VERSION 5.7 ;
  NOWIREEXTENSIONATPIN ON ;
  DIVIDERCHAR "/" ;
  BUSBITCHARS "[]" ;
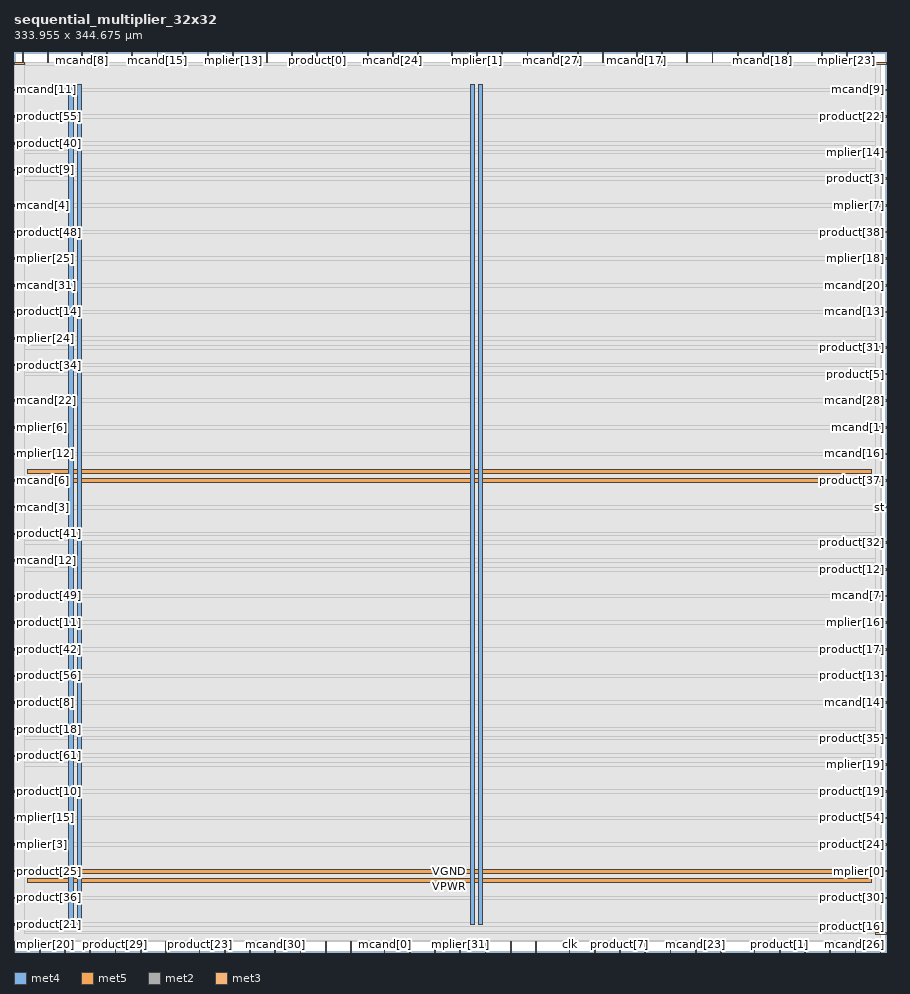
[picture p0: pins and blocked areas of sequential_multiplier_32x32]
MACRO sequential_multiplier_32x32
  CLASS BLOCK ;
  FOREIGN sequential_multiplier_32x32 ;
  ORIGIN 0.000 0.000 ;
  SIZE 333.955 BY 344.675 ;
  PIN VGND
    DIRECTION INOUT ;
    USE GROUND ;
    PORT
      LAYER met4 ;
        RECT 24.340 10.640 25.940 332.080 ;
    END
    PORT
      LAYER met4 ;
        RECT 177.940 10.640 179.540 332.080 ;
    END
    PORT
      LAYER met5 ;
        RECT 5.280 30.030 328.220 31.630 ;
    END
    PORT
      LAYER met5 ;
        RECT 5.280 183.210 328.220 184.810 ;
    END
  END VGND
  PIN VPWR
    DIRECTION INOUT ;
    USE POWER ;
    PORT
      LAYER met4 ;
        RECT 21.040 10.640 22.640 332.080 ;
    END
    PORT
      LAYER met4 ;
        RECT 174.640 10.640 176.240 332.080 ;
    END
    PORT
      LAYER met5 ;
        RECT 5.280 26.730 328.220 28.330 ;
    END
    PORT
      LAYER met5 ;
        RECT 5.280 179.910 328.220 181.510 ;
    END
  END VPWR
  PIN clk
    DIRECTION INPUT ;
    USE SIGNAL ;
    ANTENNAGATEAREA 0.852000 ;
    PORT
      LAYER met2 ;
        RECT 212.610 0.000 212.890 4.000 ;
    END
  END clk
  PIN done
    DIRECTION OUTPUT TRISTATE ;
    USE SIGNAL ;
    ANTENNADIFFAREA 0.795200 ;
    PORT
      LAYER met2 ;
        RECT 90.250 0.000 90.530 4.000 ;
    END
  END done
  PIN mcand[0]
    DIRECTION INPUT ;
    USE SIGNAL ;
    ANTENNAGATEAREA 0.213000 ;
    PORT
      LAYER met2 ;
        RECT 141.770 0.000 142.050 4.000 ;
    END
  END mcand[0]
  PIN mcand[10]
    DIRECTION INPUT ;
    USE SIGNAL ;
    ANTENNAGATEAREA 0.213000 ;
    PORT
      LAYER met2 ;
        RECT 199.730 0.000 200.010 4.000 ;
    END
  END mcand[10]
  PIN mcand[11]
    DIRECTION INPUT ;
    USE SIGNAL ;
    ANTENNAGATEAREA 0.159000 ;
    PORT
      LAYER met3 ;
        RECT 0.000 329.840 4.000 330.440 ;
    END
  END mcand[11]
  PIN mcand[12]
    DIRECTION INPUT ;
    USE SIGNAL ;
    ANTENNAGATEAREA 0.159000 ;
    PORT
      LAYER met3 ;
        RECT 0.000 149.640 4.000 150.240 ;
    END
  END mcand[12]
  PIN mcand[13]
    DIRECTION INPUT ;
    USE SIGNAL ;
    ANTENNAGATEAREA 0.213000 ;
    PORT
      LAYER met3 ;
        RECT 329.955 244.840 333.955 245.440 ;
    END
  END mcand[13]
  PIN mcand[14]
    DIRECTION INPUT ;
    USE SIGNAL ;
    ANTENNAGATEAREA 0.213000 ;
    PORT
      LAYER met3 ;
        RECT 329.955 95.240 333.955 95.840 ;
    END
  END mcand[14]
  PIN mcand[15]
    DIRECTION INPUT ;
    USE SIGNAL ;
    ANTENNAGATEAREA 0.159000 ;
    PORT
      LAYER met2 ;
        RECT 54.830 340.675 55.110 344.675 ;
    END
  END mcand[15]
  PIN mcand[16]
    DIRECTION INPUT ;
    USE SIGNAL ;
    ANTENNAGATEAREA 0.213000 ;
    PORT
      LAYER met3 ;
        RECT 329.955 190.440 333.955 191.040 ;
    END
  END mcand[16]
  PIN mcand[17]
    DIRECTION INPUT ;
    USE SIGNAL ;
    ANTENNAGATEAREA 0.196500 ;
    PORT
      LAYER met2 ;
        RECT 238.370 340.675 238.650 344.675 ;
    END
  END mcand[17]
  PIN mcand[18]
    DIRECTION INPUT ;
    USE SIGNAL ;
    ANTENNAGATEAREA 0.196500 ;
    PORT
      LAYER met2 ;
        RECT 286.670 340.675 286.950 344.675 ;
    END
  END mcand[18]
  PIN mcand[19]
    DIRECTION INPUT ;
    USE SIGNAL ;
    ANTENNAGATEAREA 0.213000 ;
    PORT
      LAYER met2 ;
        RECT 328.530 340.675 328.810 344.675 ;
    END
  END mcand[19]
  PIN mcand[1]
    DIRECTION INPUT ;
    USE SIGNAL ;
    ANTENNAGATEAREA 0.213000 ;
    PORT
      LAYER met3 ;
        RECT 329.955 200.640 333.955 201.240 ;
    END
  END mcand[1]
  PIN mcand[20]
    DIRECTION INPUT ;
    USE SIGNAL ;
    ANTENNAGATEAREA 0.126000 ;
    PORT
      LAYER met3 ;
        RECT 329.955 255.040 333.955 255.640 ;
    END
  END mcand[20]
  PIN mcand[21]
    DIRECTION INPUT ;
    USE SIGNAL ;
    ANTENNAGATEAREA 0.159000 ;
    PORT
      LAYER met2 ;
        RECT 80.590 0.000 80.870 4.000 ;
    END
  END mcand[21]
  PIN mcand[22]
    DIRECTION INPUT ;
    USE SIGNAL ;
    ANTENNAGATEAREA 0.213000 ;
    PORT
      LAYER met3 ;
        RECT 0.000 210.840 4.000 211.440 ;
    END
  END mcand[22]
  PIN mcand[23]
    DIRECTION INPUT ;
    USE SIGNAL ;
    ANTENNAGATEAREA 0.159000 ;
    PORT
      LAYER met2 ;
        RECT 260.910 0.000 261.190 4.000 ;
    END
  END mcand[23]
  PIN mcand[24]
    DIRECTION INPUT ;
    USE SIGNAL ;
    ANTENNAGATEAREA 0.213000 ;
    PORT
      LAYER met2 ;
        RECT 144.990 340.675 145.270 344.675 ;
    END
  END mcand[24]
  PIN mcand[25]
    DIRECTION INPUT ;
    USE SIGNAL ;
    ANTENNAGATEAREA 0.159000 ;
    PORT
      LAYER met2 ;
        RECT 322.090 0.000 322.370 4.000 ;
    END
  END mcand[25]
  PIN mcand[26]
    DIRECTION INPUT ;
    USE SIGNAL ;
    ANTENNAGATEAREA 0.159000 ;
    PORT
      LAYER met2 ;
        RECT 331.750 0.000 332.030 4.000 ;
    END
  END mcand[26]
  PIN mcand[27]
    DIRECTION INPUT ;
    USE SIGNAL ;
    ANTENNAGATEAREA 0.159000 ;
    PORT
      LAYER met2 ;
        RECT 206.170 340.675 206.450 344.675 ;
    END
  END mcand[27]
  PIN mcand[28]
    DIRECTION INPUT ;
    USE SIGNAL ;
    ANTENNAGATEAREA 0.213000 ;
    PORT
      LAYER met3 ;
        RECT 329.955 210.840 333.955 211.440 ;
    END
  END mcand[28]
  PIN mcand[29]
    DIRECTION INPUT ;
    USE SIGNAL ;
    ANTENNAGATEAREA 0.213000 ;
    PORT
      LAYER met2 ;
        RECT 74.150 340.675 74.430 344.675 ;
    END
  END mcand[29]
  PIN mcand[2]
    DIRECTION INPUT ;
    USE SIGNAL ;
    ANTENNAGATEAREA 0.213000 ;
    PORT
      LAYER met2 ;
        RECT 283.450 0.000 283.730 4.000 ;
    END
  END mcand[2]
  PIN mcand[30]
    DIRECTION INPUT ;
    USE SIGNAL ;
    ANTENNAGATEAREA 0.213000 ;
    PORT
      LAYER met2 ;
        RECT 99.910 0.000 100.190 4.000 ;
    END
  END mcand[30]
  PIN mcand[31]
    DIRECTION INPUT ;
    USE SIGNAL ;
    ANTENNAGATEAREA 0.126000 ;
    PORT
      LAYER met3 ;
        RECT 0.000 255.040 4.000 255.640 ;
    END
  END mcand[31]
  PIN mcand[3]
    DIRECTION INPUT ;
    USE SIGNAL ;
    ANTENNAGATEAREA 0.213000 ;
    PORT
      LAYER met3 ;
        RECT 0.000 170.040 4.000 170.640 ;
    END
  END mcand[3]
  PIN mcand[4]
    DIRECTION INPUT ;
    USE SIGNAL ;
    ANTENNAGATEAREA 0.159000 ;
    PORT
      LAYER met3 ;
        RECT 0.000 285.640 4.000 286.240 ;
    END
  END mcand[4]
  PIN mcand[5]
    DIRECTION INPUT ;
    USE SIGNAL ;
    ANTENNAGATEAREA 0.213000 ;
    PORT
      LAYER met2 ;
        RECT 125.670 340.675 125.950 344.675 ;
    END
  END mcand[5]
  PIN mcand[6]
    DIRECTION INPUT ;
    USE SIGNAL ;
    ANTENNAGATEAREA 0.159000 ;
    PORT
      LAYER met3 ;
        RECT 0.000 180.240 4.000 180.840 ;
    END
  END mcand[6]
  PIN mcand[7]
    DIRECTION INPUT ;
    USE SIGNAL ;
    ANTENNAGATEAREA 0.213000 ;
    PORT
      LAYER met3 ;
        RECT 329.955 136.040 333.955 136.640 ;
    END
  END mcand[7]
  PIN mcand[8]
    DIRECTION INPUT ;
    USE SIGNAL ;
    ANTENNAGATEAREA 0.126000 ;
    PORT
      LAYER met2 ;
        RECT 25.850 340.675 26.130 344.675 ;
    END
  END mcand[8]
  PIN mcand[9]
    DIRECTION INPUT ;
    USE SIGNAL ;
    ANTENNAGATEAREA 0.159000 ;
    PORT
      LAYER met3 ;
        RECT 329.955 329.840 333.955 330.440 ;
    END
  END mcand[9]
  PIN mplier[0]
    DIRECTION INPUT ;
    USE SIGNAL ;
    ANTENNAGATEAREA 0.213000 ;
    PORT
      LAYER met3 ;
        RECT 329.955 30.640 333.955 31.240 ;
    END
  END mplier[0]
  PIN mplier[10]
    DIRECTION INPUT ;
    USE SIGNAL ;
    ANTENNAGATEAREA 0.213000 ;
    PORT
      LAYER met2 ;
        RECT 45.170 340.675 45.450 344.675 ;
    END
  END mplier[10]
  PIN mplier[11]
    DIRECTION INPUT ;
    USE SIGNAL ;
    ANTENNAGATEAREA 0.213000 ;
    PORT
      LAYER met2 ;
        RECT 135.330 340.675 135.610 344.675 ;
    END
  END mplier[11]
  PIN mplier[12]
    DIRECTION INPUT ;
    USE SIGNAL ;
    ANTENNAGATEAREA 0.126000 ;
    PORT
      LAYER met3 ;
        RECT 0.000 190.440 4.000 191.040 ;
    END
  END mplier[12]
  PIN mplier[13]
    DIRECTION INPUT ;
    USE SIGNAL ;
    ANTENNAGATEAREA 0.213000 ;
    PORT
      LAYER met2 ;
        RECT 83.810 340.675 84.090 344.675 ;
    END
  END mplier[13]
  PIN mplier[14]
    DIRECTION INPUT ;
    USE SIGNAL ;
    ANTENNAGATEAREA 0.213000 ;
    PORT
      LAYER met3 ;
        RECT 329.955 306.040 333.955 306.640 ;
    END
  END mplier[14]
  PIN mplier[15]
    DIRECTION INPUT ;
    USE SIGNAL ;
    ANTENNAGATEAREA 0.196500 ;
    PORT
      LAYER met3 ;
        RECT 0.000 51.040 4.000 51.640 ;
    END
  END mplier[15]
  PIN mplier[16]
    DIRECTION INPUT ;
    USE SIGNAL ;
    ANTENNAGATEAREA 0.196500 ;
    PORT
      LAYER met3 ;
        RECT 329.955 125.840 333.955 126.440 ;
    END
  END mplier[16]
  PIN mplier[17]
    DIRECTION INPUT ;
    USE SIGNAL ;
    ANTENNAGATEAREA 0.159000 ;
    PORT
      LAYER met2 ;
        RECT 309.210 340.675 309.490 344.675 ;
    END
  END mplier[17]
  PIN mplier[18]
    DIRECTION INPUT ;
    USE SIGNAL ;
    ANTENNAGATEAREA 0.159000 ;
    PORT
      LAYER met3 ;
        RECT 329.955 265.240 333.955 265.840 ;
    END
  END mplier[18]
  PIN mplier[19]
    DIRECTION INPUT ;
    USE SIGNAL ;
    ANTENNAGATEAREA 0.196500 ;
    PORT
      LAYER met3 ;
        RECT 329.955 71.440 333.955 72.040 ;
    END
  END mplier[19]
  PIN mplier[1]
    DIRECTION INPUT ;
    USE SIGNAL ;
    ANTENNAGATEAREA 0.213000 ;
    PORT
      LAYER met2 ;
        RECT 177.190 340.675 177.470 344.675 ;
    END
  END mplier[1]
  PIN mplier[20]
    DIRECTION INPUT ;
    USE SIGNAL ;
    ANTENNAGATEAREA 0.213000 ;
    PORT
      LAYER met2 ;
        RECT 9.750 0.000 10.030 4.000 ;
    END
  END mplier[20]
  PIN mplier[21]
    DIRECTION INPUT ;
    USE SIGNAL ;
    ANTENNAGATEAREA 0.213000 ;
    PORT
      LAYER met2 ;
        RECT 225.490 340.675 225.770 344.675 ;
    END
  END mplier[21]
  PIN mplier[22]
    DIRECTION INPUT ;
    USE SIGNAL ;
    ANTENNAGATEAREA 0.196500 ;
    PORT
      LAYER met2 ;
        RECT 241.590 0.000 241.870 4.000 ;
    END
  END mplier[22]
  PIN mplier[23]
    DIRECTION INPUT ;
    USE SIGNAL ;
    ANTENNAGATEAREA 0.159000 ;
    PORT
      LAYER met2 ;
        RECT 318.870 340.675 319.150 344.675 ;
    END
  END mplier[23]
  PIN mplier[24]
    DIRECTION INPUT ;
    USE SIGNAL ;
    ANTENNAGATEAREA 0.159000 ;
    PORT
      LAYER met3 ;
        RECT 0.000 234.640 4.000 235.240 ;
    END
  END mplier[24]
  PIN mplier[25]
    DIRECTION INPUT ;
    USE SIGNAL ;
    ANTENNAGATEAREA 0.159000 ;
    PORT
      LAYER met3 ;
        RECT 0.000 265.240 4.000 265.840 ;
    END
  END mplier[25]
  PIN mplier[26]
    DIRECTION INPUT ;
    USE SIGNAL ;
    ANTENNAGATEAREA 0.159000 ;
    PORT
      LAYER met2 ;
        RECT 12.970 340.675 13.250 344.675 ;
    END
  END mplier[26]
  PIN mplier[27]
    DIRECTION INPUT ;
    USE SIGNAL ;
    ANTENNAGATEAREA 0.196500 ;
    PORT
      LAYER met2 ;
        RECT 128.890 0.000 129.170 4.000 ;
    END
  END mplier[27]
  PIN mplier[28]
    DIRECTION INPUT ;
    USE SIGNAL ;
    ANTENNAGATEAREA 0.213000 ;
    PORT
      LAYER met2 ;
        RECT 167.530 340.675 167.810 344.675 ;
    END
  END mplier[28]
  PIN mplier[29]
    DIRECTION INPUT ;
    USE SIGNAL ;
    ANTENNAGATEAREA 0.159000 ;
    PORT
      LAYER met2 ;
        RECT 106.350 340.675 106.630 344.675 ;
    END
  END mplier[29]
  PIN mplier[2]
    DIRECTION INPUT ;
    USE SIGNAL ;
    ANTENNAGATEAREA 0.126000 ;
    PORT
      LAYER met2 ;
        RECT 48.390 0.000 48.670 4.000 ;
    END
  END mplier[2]
  PIN mplier[30]
    DIRECTION INPUT ;
    USE SIGNAL ;
    ANTENNAGATEAREA 0.159000 ;
    PORT
      LAYER met3 ;
        RECT 329.955 340.040 333.955 340.640 ;
    END
  END mplier[30]
  PIN mplier[31]
    DIRECTION INPUT ;
    USE SIGNAL ;
    ANTENNAGATEAREA 0.196500 ;
    PORT
      LAYER met2 ;
        RECT 170.750 0.000 171.030 4.000 ;
    END
  END mplier[31]
  PIN mplier[3]
    DIRECTION INPUT ;
    USE SIGNAL ;
    ANTENNAGATEAREA 0.126000 ;
    PORT
      LAYER met3 ;
        RECT 0.000 40.840 4.000 41.440 ;
    END
  END mplier[3]
  PIN mplier[4]
    DIRECTION INPUT ;
    USE SIGNAL ;
    ANTENNAGATEAREA 0.213000 ;
    PORT
      LAYER met2 ;
        RECT 196.510 340.675 196.790 344.675 ;
    END
  END mplier[4]
  PIN mplier[5]
    DIRECTION INPUT ;
    USE SIGNAL ;
    ANTENNAGATEAREA 0.159000 ;
    PORT
      LAYER met2 ;
        RECT 257.690 340.675 257.970 344.675 ;
    END
  END mplier[5]
  PIN mplier[6]
    DIRECTION INPUT ;
    USE SIGNAL ;
    ANTENNAGATEAREA 0.213000 ;
    PORT
      LAYER met3 ;
        RECT 0.000 200.640 4.000 201.240 ;
    END
  END mplier[6]
  PIN mplier[7]
    DIRECTION INPUT ;
    USE SIGNAL ;
    ANTENNAGATEAREA 0.159000 ;
    PORT
      LAYER met3 ;
        RECT 329.955 285.640 333.955 286.240 ;
    END
  END mplier[7]
  PIN mplier[8]
    DIRECTION INPUT ;
    USE SIGNAL ;
    ANTENNAGATEAREA 0.159000 ;
    PORT
      LAYER met2 ;
        RECT 277.010 340.675 277.290 344.675 ;
    END
  END mplier[8]
  PIN mplier[9]
    DIRECTION INPUT ;
    USE SIGNAL ;
    ANTENNAGATEAREA 0.213000 ;
    PORT
      LAYER met2 ;
        RECT 35.510 340.675 35.790 344.675 ;
    END
  END mplier[9]
  PIN product[0]
    DIRECTION OUTPUT TRISTATE ;
    USE SIGNAL ;
    ANTENNADIFFAREA 0.795200 ;
    PORT
      LAYER met2 ;
        RECT 116.010 340.675 116.290 344.675 ;
    END
  END product[0]
  PIN product[10]
    DIRECTION OUTPUT TRISTATE ;
    USE SIGNAL ;
    ANTENNADIFFAREA 0.795200 ;
    PORT
      LAYER met3 ;
        RECT 0.000 61.240 4.000 61.840 ;
    END
  END product[10]
  PIN product[11]
    DIRECTION OUTPUT TRISTATE ;
    USE SIGNAL ;
    ANTENNADIFFAREA 0.795200 ;
    PORT
      LAYER met3 ;
        RECT 0.000 125.840 4.000 126.440 ;
    END
  END product[11]
  PIN product[12]
    DIRECTION OUTPUT TRISTATE ;
    USE SIGNAL ;
    ANTENNADIFFAREA 0.445500 ;
    PORT
      LAYER met3 ;
        RECT 329.955 146.240 333.955 146.840 ;
    END
  END product[12]
  PIN product[13]
    DIRECTION OUTPUT TRISTATE ;
    USE SIGNAL ;
    ANTENNADIFFAREA 0.445500 ;
    PORT
      LAYER met3 ;
        RECT 329.955 105.440 333.955 106.040 ;
    END
  END product[13]
  PIN product[14]
    DIRECTION OUTPUT TRISTATE ;
    USE SIGNAL ;
    ANTENNADIFFAREA 0.795200 ;
    PORT
      LAYER met3 ;
        RECT 0.000 244.840 4.000 245.440 ;
    END
  END product[14]
  PIN product[15]
    DIRECTION OUTPUT TRISTATE ;
    USE SIGNAL ;
    ANTENNADIFFAREA 0.795200 ;
    PORT
      LAYER met2 ;
        RECT 29.070 0.000 29.350 4.000 ;
    END
  END product[15]
  PIN product[16]
    DIRECTION OUTPUT TRISTATE ;
    USE SIGNAL ;
    ANTENNADIFFAREA 0.795200 ;
    PORT
      LAYER met3 ;
        RECT 329.955 6.840 333.955 7.440 ;
    END
  END product[16]
  PIN product[17]
    DIRECTION OUTPUT TRISTATE ;
    USE SIGNAL ;
    ANTENNADIFFAREA 0.795200 ;
    PORT
      LAYER met3 ;
        RECT 329.955 115.640 333.955 116.240 ;
    END
  END product[17]
  PIN product[18]
    DIRECTION OUTPUT TRISTATE ;
    USE SIGNAL ;
    ANTENNADIFFAREA 0.795200 ;
    PORT
      LAYER met3 ;
        RECT 0.000 85.040 4.000 85.640 ;
    END
  END product[18]
  PIN product[19]
    DIRECTION OUTPUT TRISTATE ;
    USE SIGNAL ;
    ANTENNADIFFAREA 0.795200 ;
    PORT
      LAYER met3 ;
        RECT 329.955 61.240 333.955 61.840 ;
    END
  END product[19]
  PIN product[1]
    DIRECTION OUTPUT TRISTATE ;
    USE SIGNAL ;
    ANTENNADIFFAREA 0.795200 ;
    PORT
      LAYER met2 ;
        RECT 293.110 0.000 293.390 4.000 ;
    END
  END product[1]
  PIN product[20]
    DIRECTION OUTPUT TRISTATE ;
    USE SIGNAL ;
    ANTENNADIFFAREA 0.795200 ;
    PORT
      LAYER met2 ;
        RECT 151.430 0.000 151.710 4.000 ;
    END
  END product[20]
  PIN product[21]
    DIRECTION OUTPUT TRISTATE ;
    USE SIGNAL ;
    ANTENNADIFFAREA 0.795200 ;
    PORT
      LAYER met3 ;
        RECT 0.000 10.240 4.000 10.840 ;
    END
  END product[21]
  PIN product[22]
    DIRECTION OUTPUT TRISTATE ;
    USE SIGNAL ;
    ANTENNADIFFAREA 0.445500 ;
    PORT
      LAYER met3 ;
        RECT 329.955 319.640 333.955 320.240 ;
    END
  END product[22]
  PIN product[23]
    DIRECTION OUTPUT TRISTATE ;
    USE SIGNAL ;
    ANTENNADIFFAREA 0.795200 ;
    PORT
      LAYER met2 ;
        RECT 70.930 0.000 71.210 4.000 ;
    END
  END product[23]
  PIN product[24]
    DIRECTION OUTPUT TRISTATE ;
    USE SIGNAL ;
    ANTENNADIFFAREA 0.795200 ;
    PORT
      LAYER met3 ;
        RECT 329.955 40.840 333.955 41.440 ;
    END
  END product[24]
  PIN product[25]
    DIRECTION OUTPUT TRISTATE ;
    USE SIGNAL ;
    ANTENNADIFFAREA 0.795200 ;
    PORT
      LAYER met3 ;
        RECT 0.000 30.640 4.000 31.240 ;
    END
  END product[25]
  PIN product[26]
    DIRECTION OUTPUT TRISTATE ;
    USE SIGNAL ;
    ANTENNADIFFAREA 0.795200 ;
    PORT
      LAYER met2 ;
        RECT 312.430 0.000 312.710 4.000 ;
    END
  END product[26]
  PIN product[27]
    DIRECTION OUTPUT TRISTATE ;
    USE SIGNAL ;
    ANTENNADIFFAREA 0.795200 ;
    PORT
      LAYER met2 ;
        RECT 154.650 340.675 154.930 344.675 ;
    END
  END product[27]
  PIN product[28]
    DIRECTION OUTPUT TRISTATE ;
    USE SIGNAL ;
    ANTENNADIFFAREA 0.795200 ;
    PORT
      LAYER met2 ;
        RECT 251.250 0.000 251.530 4.000 ;
    END
  END product[28]
  PIN product[29]
    DIRECTION OUTPUT TRISTATE ;
    USE SIGNAL ;
    ANTENNADIFFAREA 0.795200 ;
    PORT
      LAYER met2 ;
        RECT 38.730 0.000 39.010 4.000 ;
    END
  END product[29]
  PIN product[2]
    DIRECTION OUTPUT TRISTATE ;
    USE SIGNAL ;
    ANTENNADIFFAREA 0.795200 ;
    PORT
      LAYER met2 ;
        RECT 119.230 0.000 119.510 4.000 ;
    END
  END product[2]
  PIN product[30]
    DIRECTION OUTPUT TRISTATE ;
    USE SIGNAL ;
    ANTENNADIFFAREA 0.445500 ;
    PORT
      LAYER met3 ;
        RECT 329.955 20.440 333.955 21.040 ;
    END
  END product[30]
  PIN product[31]
    DIRECTION OUTPUT TRISTATE ;
    USE SIGNAL ;
    ANTENNADIFFAREA 0.445500 ;
    PORT
      LAYER met3 ;
        RECT 329.955 231.240 333.955 231.840 ;
    END
  END product[31]
  PIN product[32]
    DIRECTION OUTPUT TRISTATE ;
    USE SIGNAL ;
    ANTENNADIFFAREA 0.795200 ;
    PORT
      LAYER met3 ;
        RECT 329.955 156.440 333.955 157.040 ;
    END
  END product[32]
  PIN product[33]
    DIRECTION OUTPUT TRISTATE ;
    USE SIGNAL ;
    ANTENNADIFFAREA 0.795200 ;
    PORT
      LAYER met2 ;
        RECT 270.570 0.000 270.850 4.000 ;
    END
  END product[33]
  PIN product[34]
    DIRECTION OUTPUT TRISTATE ;
    USE SIGNAL ;
    ANTENNADIFFAREA 0.795200 ;
    PORT
      LAYER met3 ;
        RECT 0.000 224.440 4.000 225.040 ;
    END
  END product[34]
  PIN product[35]
    DIRECTION OUTPUT TRISTATE ;
    USE SIGNAL ;
    ANTENNADIFFAREA 0.445500 ;
    PORT
      LAYER met3 ;
        RECT 329.955 81.640 333.955 82.240 ;
    END
  END product[35]
  PIN product[36]
    DIRECTION OUTPUT TRISTATE ;
    USE SIGNAL ;
    ANTENNADIFFAREA 0.795200 ;
    PORT
      LAYER met3 ;
        RECT 0.000 20.440 4.000 21.040 ;
    END
  END product[36]
  PIN product[37]
    DIRECTION OUTPUT TRISTATE ;
    USE SIGNAL ;
    ANTENNADIFFAREA 0.445500 ;
    PORT
      LAYER met3 ;
        RECT 329.955 180.240 333.955 180.840 ;
    END
  END product[37]
  PIN product[38]
    DIRECTION OUTPUT TRISTATE ;
    USE SIGNAL ;
    ANTENNADIFFAREA 0.795200 ;
    PORT
      LAYER met3 ;
        RECT 329.955 275.440 333.955 276.040 ;
    END
  END product[38]
  PIN product[39]
    DIRECTION OUTPUT TRISTATE ;
    USE SIGNAL ;
    ANTENNADIFFAREA 0.795200 ;
    PORT
      LAYER met2 ;
        RECT 302.770 0.000 303.050 4.000 ;
    END
  END product[39]
  PIN product[3]
    DIRECTION OUTPUT TRISTATE ;
    USE SIGNAL ;
    ANTENNADIFFAREA 0.795200 ;
    PORT
      LAYER met3 ;
        RECT 329.955 295.840 333.955 296.440 ;
    END
  END product[3]
  PIN product[40]
    DIRECTION OUTPUT TRISTATE ;
    USE SIGNAL ;
    ANTENNADIFFAREA 0.795200 ;
    PORT
      LAYER met3 ;
        RECT 0.000 309.440 4.000 310.040 ;
    END
  END product[40]
  PIN product[41]
    DIRECTION OUTPUT TRISTATE ;
    USE SIGNAL ;
    ANTENNADIFFAREA 0.795200 ;
    PORT
      LAYER met3 ;
        RECT 0.000 159.840 4.000 160.440 ;
    END
  END product[41]
  PIN product[42]
    DIRECTION OUTPUT TRISTATE ;
    USE SIGNAL ;
    ANTENNADIFFAREA 0.795200 ;
    PORT
      LAYER met3 ;
        RECT 0.000 115.640 4.000 116.240 ;
    END
  END product[42]
  PIN product[43]
    DIRECTION OUTPUT TRISTATE ;
    USE SIGNAL ;
    ANTENNADIFFAREA 0.795200 ;
    PORT
      LAYER met2 ;
        RECT 0.090 0.000 0.370 4.000 ;
    END
  END product[43]
  PIN product[44]
    DIRECTION OUTPUT TRISTATE ;
    USE SIGNAL ;
    ANTENNADIFFAREA 0.795200 ;
    PORT
      LAYER met2 ;
        RECT 222.270 0.000 222.550 4.000 ;
    END
  END product[44]
  PIN product[45]
    DIRECTION OUTPUT TRISTATE ;
    USE SIGNAL ;
    ANTENNADIFFAREA 0.795200 ;
    PORT
      LAYER met3 ;
        RECT 0.000 340.040 4.000 340.640 ;
    END
  END product[45]
  PIN product[46]
    DIRECTION OUTPUT TRISTATE ;
    USE SIGNAL ;
    ANTENNADIFFAREA 0.795200 ;
    PORT
      LAYER met2 ;
        RECT 96.690 340.675 96.970 344.675 ;
    END
  END product[46]
  PIN product[47]
    DIRECTION OUTPUT TRISTATE ;
    USE SIGNAL ;
    ANTENNADIFFAREA 0.795200 ;
    PORT
      LAYER met2 ;
        RECT 215.830 340.675 216.110 344.675 ;
    END
  END product[47]
  PIN product[48]
    DIRECTION OUTPUT TRISTATE ;
    USE SIGNAL ;
    ANTENNADIFFAREA 0.795200 ;
    PORT
      LAYER met3 ;
        RECT 0.000 275.440 4.000 276.040 ;
    END
  END product[48]
  PIN product[49]
    DIRECTION OUTPUT TRISTATE ;
    USE SIGNAL ;
    ANTENNADIFFAREA 0.795200 ;
    PORT
      LAYER met3 ;
        RECT 0.000 136.040 4.000 136.640 ;
    END
  END product[49]
  PIN product[4]
    DIRECTION OUTPUT TRISTATE ;
    USE SIGNAL ;
    ANTENNADIFFAREA 0.795200 ;
    PORT
      LAYER met2 ;
        RECT 19.410 0.000 19.690 4.000 ;
    END
  END product[4]
  PIN product[50]
    DIRECTION OUTPUT TRISTATE ;
    USE SIGNAL ;
    ANTENNADIFFAREA 0.795200 ;
    PORT
      LAYER met2 ;
        RECT 267.350 340.675 267.630 344.675 ;
    END
  END product[50]
  PIN product[51]
    DIRECTION OUTPUT TRISTATE ;
    USE SIGNAL ;
    ANTENNADIFFAREA 0.795200 ;
    PORT
      LAYER met2 ;
        RECT 186.850 340.675 187.130 344.675 ;
    END
  END product[51]
  PIN product[52]
    DIRECTION OUTPUT TRISTATE ;
    USE SIGNAL ;
    ANTENNADIFFAREA 0.795200 ;
    PORT
      LAYER met2 ;
        RECT 161.090 0.000 161.370 4.000 ;
    END
  END product[52]
  PIN product[53]
    DIRECTION OUTPUT TRISTATE ;
    USE SIGNAL ;
    ANTENNADIFFAREA 0.795200 ;
    PORT
      LAYER met2 ;
        RECT 296.330 340.675 296.610 344.675 ;
    END
  END product[53]
  PIN product[54]
    DIRECTION OUTPUT TRISTATE ;
    USE SIGNAL ;
    ANTENNADIFFAREA 0.445500 ;
    PORT
      LAYER met3 ;
        RECT 329.955 51.040 333.955 51.640 ;
    END
  END product[54]
  PIN product[55]
    DIRECTION OUTPUT TRISTATE ;
    USE SIGNAL ;
    ANTENNADIFFAREA 0.795200 ;
    PORT
      LAYER met3 ;
        RECT 0.000 319.640 4.000 320.240 ;
    END
  END product[55]
  PIN product[56]
    DIRECTION OUTPUT TRISTATE ;
    USE SIGNAL ;
    ANTENNADIFFAREA 0.795200 ;
    PORT
      LAYER met3 ;
        RECT 0.000 105.440 4.000 106.040 ;
    END
  END product[56]
  PIN product[57]
    DIRECTION OUTPUT TRISTATE ;
    USE SIGNAL ;
    ANTENNADIFFAREA 0.795200 ;
    PORT
      LAYER met2 ;
        RECT 58.050 0.000 58.330 4.000 ;
    END
  END product[57]
  PIN product[58]
    DIRECTION OUTPUT TRISTATE ;
    USE SIGNAL ;
    ANTENNADIFFAREA 0.795200 ;
    PORT
      LAYER met2 ;
        RECT 109.570 0.000 109.850 4.000 ;
    END
  END product[58]
  PIN product[59]
    DIRECTION OUTPUT TRISTATE ;
    USE SIGNAL ;
    ANTENNADIFFAREA 0.795200 ;
    PORT
      LAYER met2 ;
        RECT 180.410 0.000 180.690 4.000 ;
    END
  END product[59]
  PIN product[5]
    DIRECTION OUTPUT TRISTATE ;
    USE SIGNAL ;
    ANTENNADIFFAREA 0.445500 ;
    PORT
      LAYER met3 ;
        RECT 329.955 221.040 333.955 221.640 ;
    END
  END product[5]
  PIN product[60]
    DIRECTION OUTPUT TRISTATE ;
    USE SIGNAL ;
    ANTENNADIFFAREA 0.795200 ;
    PORT
      LAYER met2 ;
        RECT 190.070 0.000 190.350 4.000 ;
    END
  END product[60]
  PIN product[61]
    DIRECTION OUTPUT TRISTATE ;
    USE SIGNAL ;
    ANTENNADIFFAREA 0.795200 ;
    PORT
      LAYER met3 ;
        RECT 0.000 74.840 4.000 75.440 ;
    END
  END product[61]
  PIN product[62]
    DIRECTION OUTPUT TRISTATE ;
    USE SIGNAL ;
    ANTENNADIFFAREA 0.795200 ;
    PORT
      LAYER met2 ;
        RECT 248.030 340.675 248.310 344.675 ;
    END
  END product[62]
  PIN product[63]
    DIRECTION OUTPUT TRISTATE ;
    USE SIGNAL ;
    ANTENNADIFFAREA 0.795200 ;
    PORT
      LAYER met2 ;
        RECT 3.310 340.675 3.590 344.675 ;
    END
  END product[63]
  PIN product[6]
    DIRECTION OUTPUT TRISTATE ;
    USE SIGNAL ;
    ANTENNADIFFAREA 0.795200 ;
    PORT
      LAYER met2 ;
        RECT 64.490 340.675 64.770 344.675 ;
    END
  END product[6]
  PIN product[7]
    DIRECTION OUTPUT TRISTATE ;
    USE SIGNAL ;
    ANTENNADIFFAREA 0.795200 ;
    PORT
      LAYER met2 ;
        RECT 231.930 0.000 232.210 4.000 ;
    END
  END product[7]
  PIN product[8]
    DIRECTION OUTPUT TRISTATE ;
    USE SIGNAL ;
    ANTENNADIFFAREA 0.795200 ;
    PORT
      LAYER met3 ;
        RECT 0.000 95.240 4.000 95.840 ;
    END
  END product[8]
  PIN product[9]
    DIRECTION OUTPUT TRISTATE ;
    USE SIGNAL ;
    ANTENNADIFFAREA 0.795200 ;
    PORT
      LAYER met3 ;
        RECT 0.000 299.240 4.000 299.840 ;
    END
  END product[9]
  PIN st
    DIRECTION INPUT ;
    USE SIGNAL ;
    ANTENNAGATEAREA 0.213000 ;
    PORT
      LAYER met3 ;
        RECT 329.955 170.040 333.955 170.640 ;
    END
  END st
  OBS
      LAYER li1 ;
        RECT 5.520 10.795 327.980 331.925 ;
      LAYER met1 ;
        RECT 0.070 6.840 332.050 332.080 ;
      LAYER met2 ;
        RECT 0.100 340.395 3.030 340.675 ;
        RECT 3.870 340.395 12.690 340.675 ;
        RECT 13.530 340.395 25.570 340.675 ;
        RECT 26.410 340.395 35.230 340.675 ;
        RECT 36.070 340.395 44.890 340.675 ;
        RECT 45.730 340.395 54.550 340.675 ;
        RECT 55.390 340.395 64.210 340.675 ;
        RECT 65.050 340.395 73.870 340.675 ;
        RECT 74.710 340.395 83.530 340.675 ;
        RECT 84.370 340.395 96.410 340.675 ;
        RECT 97.250 340.395 106.070 340.675 ;
        RECT 106.910 340.395 115.730 340.675 ;
        RECT 116.570 340.395 125.390 340.675 ;
        RECT 126.230 340.395 135.050 340.675 ;
        RECT 135.890 340.395 144.710 340.675 ;
        RECT 145.550 340.395 154.370 340.675 ;
        RECT 155.210 340.395 167.250 340.675 ;
        RECT 168.090 340.395 176.910 340.675 ;
        RECT 177.750 340.395 186.570 340.675 ;
        RECT 187.410 340.395 196.230 340.675 ;
        RECT 197.070 340.395 205.890 340.675 ;
        RECT 206.730 340.395 215.550 340.675 ;
        RECT 216.390 340.395 225.210 340.675 ;
        RECT 226.050 340.395 238.090 340.675 ;
        RECT 238.930 340.395 247.750 340.675 ;
        RECT 248.590 340.395 257.410 340.675 ;
        RECT 258.250 340.395 267.070 340.675 ;
        RECT 267.910 340.395 276.730 340.675 ;
        RECT 277.570 340.395 286.390 340.675 ;
        RECT 287.230 340.395 296.050 340.675 ;
        RECT 296.890 340.395 308.930 340.675 ;
        RECT 309.770 340.395 318.590 340.675 ;
        RECT 319.430 340.395 328.250 340.675 ;
        RECT 329.090 340.395 332.020 340.675 ;
        RECT 0.100 4.280 332.020 340.395 ;
        RECT 0.650 4.000 9.470 4.280 ;
        RECT 10.310 4.000 19.130 4.280 ;
        RECT 19.970 4.000 28.790 4.280 ;
        RECT 29.630 4.000 38.450 4.280 ;
        RECT 39.290 4.000 48.110 4.280 ;
        RECT 48.950 4.000 57.770 4.280 ;
        RECT 58.610 4.000 70.650 4.280 ;
        RECT 71.490 4.000 80.310 4.280 ;
        RECT 81.150 4.000 89.970 4.280 ;
        RECT 90.810 4.000 99.630 4.280 ;
        RECT 100.470 4.000 109.290 4.280 ;
        RECT 110.130 4.000 118.950 4.280 ;
        RECT 119.790 4.000 128.610 4.280 ;
        RECT 129.450 4.000 141.490 4.280 ;
        RECT 142.330 4.000 151.150 4.280 ;
        RECT 151.990 4.000 160.810 4.280 ;
        RECT 161.650 4.000 170.470 4.280 ;
        RECT 171.310 4.000 180.130 4.280 ;
        RECT 180.970 4.000 189.790 4.280 ;
        RECT 190.630 4.000 199.450 4.280 ;
        RECT 200.290 4.000 212.330 4.280 ;
        RECT 213.170 4.000 221.990 4.280 ;
        RECT 222.830 4.000 231.650 4.280 ;
        RECT 232.490 4.000 241.310 4.280 ;
        RECT 242.150 4.000 250.970 4.280 ;
        RECT 251.810 4.000 260.630 4.280 ;
        RECT 261.470 4.000 270.290 4.280 ;
        RECT 271.130 4.000 283.170 4.280 ;
        RECT 284.010 4.000 292.830 4.280 ;
        RECT 293.670 4.000 302.490 4.280 ;
        RECT 303.330 4.000 312.150 4.280 ;
        RECT 312.990 4.000 321.810 4.280 ;
        RECT 322.650 4.000 331.470 4.280 ;
      LAYER met3 ;
        RECT 4.400 339.640 329.555 340.505 ;
        RECT 3.990 330.840 329.955 339.640 ;
        RECT 4.400 329.440 329.555 330.840 ;
        RECT 3.990 320.640 329.955 329.440 ;
        RECT 4.400 319.240 329.555 320.640 ;
        RECT 3.990 310.440 329.955 319.240 ;
        RECT 4.400 309.040 329.955 310.440 ;
        RECT 3.990 307.040 329.955 309.040 ;
        RECT 3.990 305.640 329.555 307.040 ;
        RECT 3.990 300.240 329.955 305.640 ;
        RECT 4.400 298.840 329.955 300.240 ;
        RECT 3.990 296.840 329.955 298.840 ;
        RECT 3.990 295.440 329.555 296.840 ;
        RECT 3.990 286.640 329.955 295.440 ;
        RECT 4.400 285.240 329.555 286.640 ;
        RECT 3.990 276.440 329.955 285.240 ;
        RECT 4.400 275.040 329.555 276.440 ;
        RECT 3.990 266.240 329.955 275.040 ;
        RECT 4.400 264.840 329.555 266.240 ;
        RECT 3.990 256.040 329.955 264.840 ;
        RECT 4.400 254.640 329.555 256.040 ;
        RECT 3.990 245.840 329.955 254.640 ;
        RECT 4.400 244.440 329.555 245.840 ;
        RECT 3.990 235.640 329.955 244.440 ;
        RECT 4.400 234.240 329.955 235.640 ;
        RECT 3.990 232.240 329.955 234.240 ;
        RECT 3.990 230.840 329.555 232.240 ;
        RECT 3.990 225.440 329.955 230.840 ;
        RECT 4.400 224.040 329.955 225.440 ;
        RECT 3.990 222.040 329.955 224.040 ;
        RECT 3.990 220.640 329.555 222.040 ;
        RECT 3.990 211.840 329.955 220.640 ;
        RECT 4.400 210.440 329.555 211.840 ;
        RECT 3.990 201.640 329.955 210.440 ;
        RECT 4.400 200.240 329.555 201.640 ;
        RECT 3.990 191.440 329.955 200.240 ;
        RECT 4.400 190.040 329.555 191.440 ;
        RECT 3.990 181.240 329.955 190.040 ;
        RECT 4.400 179.840 329.555 181.240 ;
        RECT 3.990 171.040 329.955 179.840 ;
        RECT 4.400 169.640 329.555 171.040 ;
        RECT 3.990 160.840 329.955 169.640 ;
        RECT 4.400 159.440 329.955 160.840 ;
        RECT 3.990 157.440 329.955 159.440 ;
        RECT 3.990 156.040 329.555 157.440 ;
        RECT 3.990 150.640 329.955 156.040 ;
        RECT 4.400 149.240 329.955 150.640 ;
        RECT 3.990 147.240 329.955 149.240 ;
        RECT 3.990 145.840 329.555 147.240 ;
        RECT 3.990 137.040 329.955 145.840 ;
        RECT 4.400 135.640 329.555 137.040 ;
        RECT 3.990 126.840 329.955 135.640 ;
        RECT 4.400 125.440 329.555 126.840 ;
        RECT 3.990 116.640 329.955 125.440 ;
        RECT 4.400 115.240 329.555 116.640 ;
        RECT 3.990 106.440 329.955 115.240 ;
        RECT 4.400 105.040 329.555 106.440 ;
        RECT 3.990 96.240 329.955 105.040 ;
        RECT 4.400 94.840 329.555 96.240 ;
        RECT 3.990 86.040 329.955 94.840 ;
        RECT 4.400 84.640 329.955 86.040 ;
        RECT 3.990 82.640 329.955 84.640 ;
        RECT 3.990 81.240 329.555 82.640 ;
        RECT 3.990 75.840 329.955 81.240 ;
        RECT 4.400 74.440 329.955 75.840 ;
        RECT 3.990 72.440 329.955 74.440 ;
        RECT 3.990 71.040 329.555 72.440 ;
        RECT 3.990 62.240 329.955 71.040 ;
        RECT 4.400 60.840 329.555 62.240 ;
        RECT 3.990 52.040 329.955 60.840 ;
        RECT 4.400 50.640 329.555 52.040 ;
        RECT 3.990 41.840 329.955 50.640 ;
        RECT 4.400 40.440 329.555 41.840 ;
        RECT 3.990 31.640 329.955 40.440 ;
        RECT 4.400 30.240 329.555 31.640 ;
        RECT 3.990 21.440 329.955 30.240 ;
        RECT 4.400 20.040 329.555 21.440 ;
        RECT 3.990 11.240 329.955 20.040 ;
        RECT 4.400 9.840 329.955 11.240 ;
        RECT 3.990 7.840 329.955 9.840 ;
        RECT 3.990 6.975 329.555 7.840 ;
  END
END sequential_multiplier_32x32
END LIBRARY

